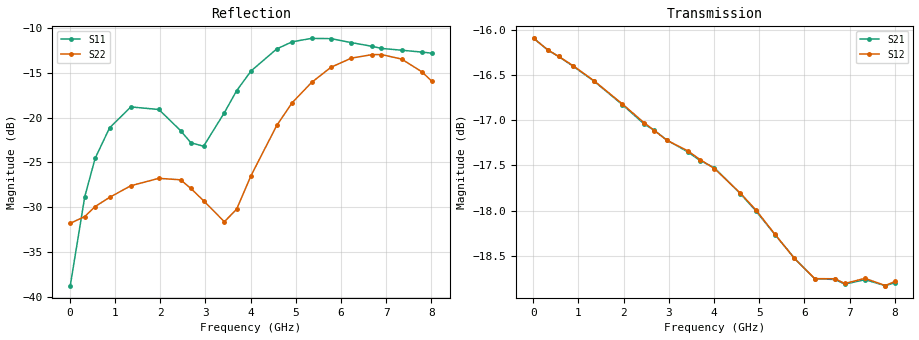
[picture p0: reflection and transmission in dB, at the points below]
!Agilent Technologies,E5071B,MY42404982,A.09.10
!Date: Mon Oct 20 13:34:15 2025
!Data & Calibration Information:
!Freq	S11:SOLT2(ON)	S21:SOLT2(ON)	S12:SOLT2(ON)	S22:SOLT2(ON)
# Hz S RI R 50
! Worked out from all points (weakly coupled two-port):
!   801 points, 10 MHz to 8.01 GHz, reference 50 ohm
!   highest |S21| = -16.10 dB at 10 MHz (marker M1); lowest = -18.8 dB at 7.79 GHz (marker M2)
!   lowest |S11| = -38.7 dB at 10 MHz (marker M3), VSWR 1.02, Z = 48.9 - j0.173 ohm
!   |S11| at or under -10 dB: start of sweep to end of sweep
!   |S22| runs from -31.8 to -12.9 dB; largest |S21 - S12| = 0.0011
!   S11 on the Smith chart (normalised r, x): 10 MHz: 0.98, -0.00; 4.58 GHz: 0.62, +0.11; 5.78 GHz: 1.15, +0.60; 6.89 GHz: 1.34, -0.47; 8.01 GHz: 0.64, -0.13
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1e7  -0.0114 -0.00177  0.1567 -0.00339  0.1567 -0.00357  0.0257 -0.000881
3.3e8  -0.0232 -0.0277  0.1276 -0.0869  0.1275 -0.0871  0.0226 -0.0166
5.6e8  -0.0439 -0.0398  0.0818 -0.1295  0.0817 -0.1296  0.0145 -0.0284
8.8e8  -0.081 -0.0336  -0.000775 -0.1513  -0.000871 -0.1514  -0.00792 -0.035
1.35e9  -0.1122 0.0237  -0.1101 -0.0995  -0.1102 -0.0995  -0.0383 -0.0164
1.97e9  -0.0483 0.0999  -0.1352 0.0498  -0.1353 0.0499  -0.0327 0.0321
2.45e9  0.0364 0.0764  -0.0528 0.1303  -0.0529 0.1305  0.00247 0.0449
2.68e9  0.0623 0.0367  0.00165 0.1394  0.00156 0.1394  0.0187 0.0356
2.96e9  0.0649 -0.0241  0.0652 0.1213  0.0653 0.1212  0.0295 0.0176
3.42e9  -0.00365 -0.1065  0.1302 0.0381  0.1304 0.0381  0.0184 -0.0187
3.69e9  -0.0742 -0.12  0.132 -0.0241  0.1321 -0.0245  -0.00366 -0.0306
4.01e9  -0.1609 -0.0853  0.0985 -0.0893  0.0985 -0.0891  -0.0384 -0.0279
4.58e9  -0.2264 0.0849  -0.02 -0.1271  -0.0199 -0.1272  -0.0832 0.0357
4.92e9  -0.1763 0.1975  -0.0851 -0.0928  -0.0849 -0.0932  -0.0753 0.0948
5.35e9  -0.0317 0.2749  -0.1216 -0.0111  -0.1216 -0.0116  -0.013 0.1566
5.78e9  0.1371 0.2392  -0.0954 0.0703  -0.0953 0.0704  0.088 0.1695
6.23e9  0.2457 0.091  -0.0217 0.1134  -0.0207 0.1136  0.187 0.1054
6.68e9  0.2315 -0.0944  0.0621 0.0972  0.0623 0.0972  0.2241 -0.012
6.89e9  0.1786 -0.1652  0.0912 0.0695  0.0914 0.0694  0.2129 -0.0723
7.34e9  0.00661 -0.2376  0.1146 -0.0128  0.1148 -0.0128  0.1315 -0.1665
7.79e9  -0.1623 -0.1658  0.0734 -0.0878  0.0732 -0.088  0.00916 -0.1798
8.01e9  -0.2092 -0.0924  0.0357 -0.1092  0.036 -0.1093  -0.0418 -0.154
